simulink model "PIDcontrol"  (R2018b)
settings: Solver=ode45  StartTime=0.0  StopTime=10.0  RelTol=1e-3  EnableMultiTasking=on
libraries: legoev3lib x2, simulink x1

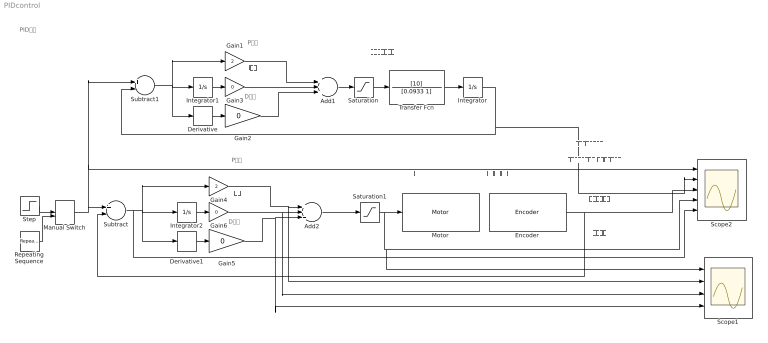
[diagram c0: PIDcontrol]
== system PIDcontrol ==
  note: モータのモデル
  note: PID制御
  note: モータへ入力
  note: モータの角度
  note: P制御
  note: I制御
  note: D制御
  note: P制御
  note: D制御
  note: I制御
  note: シミュレーション のモータの角度
  note: モータの目標角度
  note: モータの角度
  note: 制御入力
  Add1 : Sum  Inputs=+++
  Add2 : Sum  Inputs=+++
  Derivative : Derivative
  Derivative1 : Derivative
  Encoder : legoev3lib/Encoder  portNumber=B  opMode=No reset  sampleTime=0.01
  Gain1 : Gain  Gain=2
  Gain{2..3,5..6} (4 alike) : Gain  Gain=0
  Gain4 : Gain  Gain=2
  Integrator : Integrator
  Integrator1 : Integrator
  Integrator2 : Integrator
  Manual Switch : ManualSwitch  CurrentSetting=0
  Motor : legoev3lib/Motor  sportNumber=B  sstopAction=Brake
  Repeating Sequence : simulink/Sources/Repeating Sequence  rep_seq_t=[0 6]  rep_seq_y=[0 360*4]
  Saturation : Saturate  UpperLimit=100  LowerLimit=-100
  Saturation1 : Saturate  UpperLimit=100  LowerLimit=-100
  Scope1 : Scope  NumInputPorts=4
  Scope2 : Scope  NumInputPorts=5
  Step : Step  After=360  SampleTime=0
  Subtract : Sum  Inputs=+-
  Subtract1 : Sum  Inputs=+-
  Transfer Fcn : TransferFcn  Numerator=[10]  Denominator=[0.0933 1]
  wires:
  Encoder/1 -> Subtract/2, Scope2/3
  Saturation1/1 -> Scope1/1, Scope2/4, Motor/1
  Transfer Fcn/1 -> Integrator/1
  Saturation/1 -> Transfer Fcn/1
  Integrator/1 -> Scope2/2, Subtract1/2
  Gain1/1 -> Add1/1
  Add1/1 -> Saturation/1
  Subtract1/1 -> Derivative/1, Gain1/1, Integrator1/1
  Integrator1/1 -> Gain3/1
  Derivative/1 -> Gain2/1
  Gain2/1 -> Add1/3
  Gain3/1 -> Add1/2
  Integrator2/1 -> Gain6/1
  Gain6/1 -> Scope1/3, Add2/2
  Gain5/1 -> Scope1/4, Add2/3
  Derivative1/1 -> Gain5/1
  Gain4/1 -> Scope1/2, Add2/1
  Step/1 -> Manual Switch/1
  Repeating Sequence/1 -> Manual Switch/2
  Manual Switch/1 -> Scope2/1, Subtract1/1, Subtract/1
  Add2/1 -> Saturation1/1
  Subtract/1 -> Scope2/5, Integrator2/1, Derivative1/1, Gain4/1
